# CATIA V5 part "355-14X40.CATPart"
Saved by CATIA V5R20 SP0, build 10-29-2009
Part number: 355-14X40
Definition: NONE
Nomenclature: 355-14X40
Source: Unknown
Description: 355-14X40
Bounding box of the stored display mesh (mm): x -21 to 19, y -12 to 12, z -12 to 12
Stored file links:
  C:\Users\Utente\Desktop\IO LAVORO\3D X SITO CF\X SITO\PLASTICA\355\355-14X40.CATPart

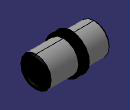
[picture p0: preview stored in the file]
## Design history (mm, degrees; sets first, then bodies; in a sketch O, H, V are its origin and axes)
Body1 "355-14X40" (main body)
  Solid1: solid without history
